One B-rep face of a CAD part: STEP entity #113.
In plain terms, the planar face has unit normal (-1, 0, 0).
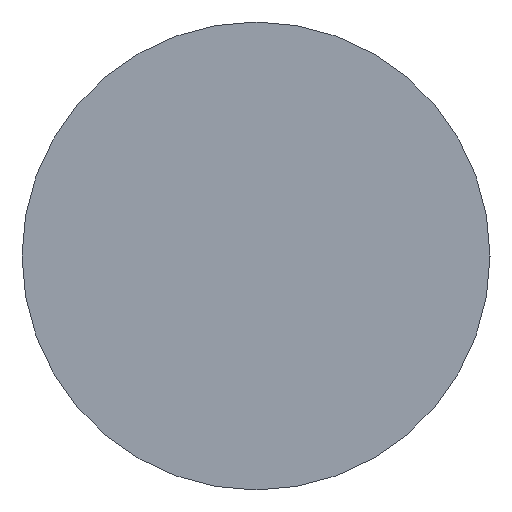
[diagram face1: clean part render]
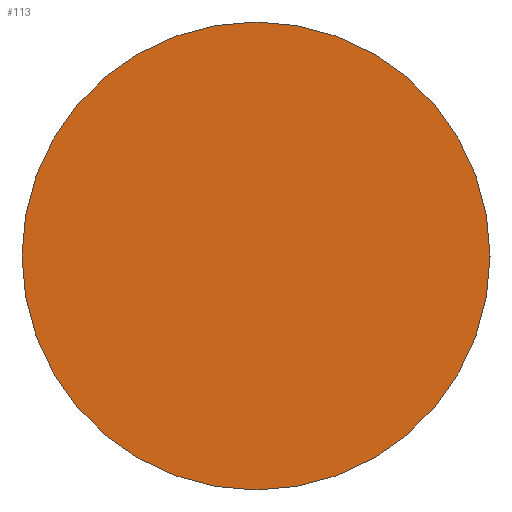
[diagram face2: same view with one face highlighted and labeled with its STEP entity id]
Its self-contained STEP definition (entity closure, numbers rounded to 3 decimals):
#21 = EDGE_CURVE('',#22,#22,#24,.T.);
#22 = VERTEX_POINT('',#23);
#23 = CARTESIAN_POINT('',(-6.9,50.,20.));
#24 = SURFACE_CURVE('',#25,(#30,#42),.PCURVE_S1.);
#25 = CIRCLE('',#26,1.);
#26 = AXIS2_PLACEMENT_3D('',#27,#28,#29);
#27 = CARTESIAN_POINT('',(-6.9,50.,19.));
#28 = DIRECTION('',(1.,-0.,0.));
#29 = DIRECTION('',(-0.,-0.,1.));
#30 = PCURVE('',#31,#36);
#31 = CYLINDRICAL_SURFACE('',#32,1.);
#32 = AXIS2_PLACEMENT_3D('',#33,#34,#35);
#33 = CARTESIAN_POINT('',(6.9,50.,19.));
#34 = DIRECTION('',(-1.,-0.,-0.));
#35 = DIRECTION('',(-0.,-0.,1.));
#36 = DEFINITIONAL_REPRESENTATION('',(#37),#41);
#37 = LINE('',#38,#39);
#38 = CARTESIAN_POINT('',(-0.,13.8));
#39 = VECTOR('',#40,1.);
#40 = DIRECTION('',(-1.,0.));
#41 = ( GEOMETRIC_REPRESENTATION_CONTEXT(2) 
PARAMETRIC_REPRESENTATION_CONTEXT() REPRESENTATION_CONTEXT('2D SPACE',''
  ) );
#42 = PCURVE('',#43,#48);
#43 = PLANE('',#44);
#44 = AXIS2_PLACEMENT_3D('',#45,#46,#47);
#45 = CARTESIAN_POINT('',(-6.9,50.,19.));
#46 = DIRECTION('',(-1.,-0.,-0.));
#47 = DIRECTION('',(0.,0.,-1.));
#48 = DEFINITIONAL_REPRESENTATION('',(#49),#57);
#49 = ( BOUNDED_CURVE() B_SPLINE_CURVE(2,(#50,#51,#52,#53,#54,#55,#56),
.UNSPECIFIED.,.T.,.F.) B_SPLINE_CURVE_WITH_KNOTS((1,2,2,2,2,1),(
    -2.094,0.,2.094,4.189,6.283,
8.378),.UNSPECIFIED.) CURVE() GEOMETRIC_REPRESENTATION_ITEM() 
RATIONAL_B_SPLINE_CURVE((1.,0.5,1.,0.5,1.,0.5,1.)) REPRESENTATION_ITEM(
  '') );
#50 = CARTESIAN_POINT('',(-1.,0.));
#51 = CARTESIAN_POINT('',(-1.,1.732));
#52 = CARTESIAN_POINT('',(0.5,0.866));
#53 = CARTESIAN_POINT('',(2.,0.));
#54 = CARTESIAN_POINT('',(0.5,-0.866));
#55 = CARTESIAN_POINT('',(-1.,-1.732));
#56 = CARTESIAN_POINT('',(-1.,0.));
#57 = ( GEOMETRIC_REPRESENTATION_CONTEXT(2) 
PARAMETRIC_REPRESENTATION_CONTEXT() REPRESENTATION_CONTEXT('2D SPACE',''
  ) );
#113 = ADVANCED_FACE('',(#114),#43,.T.);
#114 = FACE_BOUND('',#115,.F.);
#115 = EDGE_LOOP('',(#116));
#116 = ORIENTED_EDGE('',*,*,#21,.T.);
